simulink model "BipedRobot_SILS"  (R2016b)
settings: Solver=ode23tb  StartTime=0.0  StopTime=Tend  FixedStep=0.001  RelTol=1e-4  EnableMultiTasking=on
PreLoadFcn:
  | BipedRobot_param
  | load walk_forward
  | eta = 1;
  | N = 40;
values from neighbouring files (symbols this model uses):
  A = [1 0 0 0 0 0    [symbolic_sample.m]
  bn = 50    [BipedRobot_param.m]    (also in SimpleContact_param.m)
  bt = 50    [BipedRobot_param.m]    (also in SimpleContact_param.m)
  kn = 5000    [BipedRobot_param.m]    (also in SimpleContact_param.m)
  kt = 5000    [BipedRobot_param.m]    (also in SimpleContact_param.m)
  mu_d = 0.8    [BipedRobot_param.m]    (also in SimpleContact_param.m)
  mu_s = 2    [BipedRobot_param.m]    (also in SimpleContact_param.m)
  s = robot_para.s    [kinematics_calc.m]    (also in plot_graph.m; robot_parameter.m = 40; robot_view.m)
  Ts = walk_para.Ts    [Angular_Vel_Acc_calc_forward.m]    (also in main.m; reference_orbit.m; reference_orbit_acc.m; Vel_Acc_calc_forward.m)
  zvt = 1e-3    (= 0.001)    [BipedRobot_param.m]    (also in SimpleContact_param.m)
undefined symbols (not defined in the file or in its folder): arm, bridge, constant, deg, Inertia, KD, kg, KI, KP, m, Mass, powergui, pulses, rad, S, Torque
libraries: mblibv1 x90, powerlib x7, simulink x2, powerlib_extras x1
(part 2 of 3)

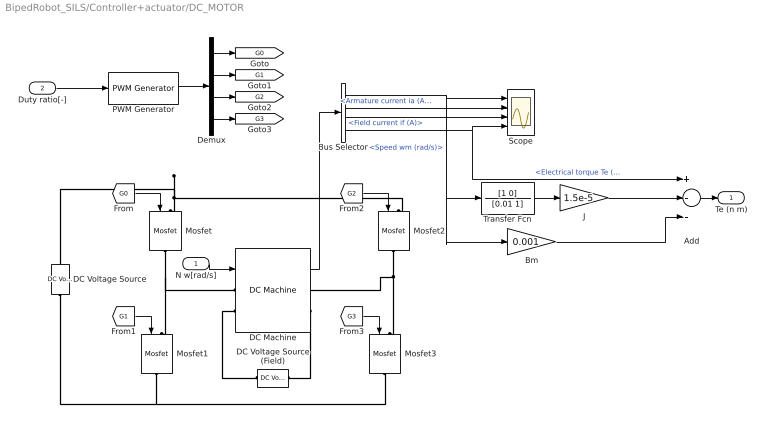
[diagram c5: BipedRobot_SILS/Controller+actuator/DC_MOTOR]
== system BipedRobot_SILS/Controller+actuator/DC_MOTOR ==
  N w[rad/s] : Inport
  Duty ratio[-] : Inport  Port=2
  Add : Sum  Inputs=+--
  Bm : Gain  Gain=0.001
  Bus Selector : BusSelector  OutputSignals=Speed wm (rad/s),Armature current ia (A),Field current if (A),Electrical torque Te (n m)
  DC Machine : powerlib/Machines/DC Machine  PresetModel=No  MechanicalLoad=Speed w  FieldType=Wound  ShowDetailedParameters=on  MeasurementBus=off  RLa="[ 10  4.4e-3]"  RLf="[ 24  0 ]"  Laf=0.05  MachineConstant=Torque constant (N.m/A)  Ke=1.8  Kt=1.8  J=1.5e-5  Bm=0.001  Tf=0  w0=0  Ifinit=1  TsPowergui=0  TsBlock=-1
  DC Voltage Source : powerlib/Electrical Sources/DC Voltage Source  Amplitude=24  Measurements=None
  DC Voltage Source (Field) : powerlib/Electrical Sources/DC Voltage Source  Amplitude=24  Measurements=None
  Demux : Demux
  J : Gain  Gain=1.5e-5
  Mosfet{,1..3} (4 alike) : powerlib/Power Electronics/Mosfet  Ron=0.3  Lon=0  Rd=0.01  Vfd=0  IC=0  Rs=5e9  Cs=inf  Measurements=off
  PWM Generator : powerlib_extras/Control  Blocks/PWM Generator  GeneratorMode="2-arm  bridge (4 pulses)"  Fc=1000  Internal=off  mIndex=0.4  Freq=60  Phase=0
  Scope : Scope  NumInputPorts=4
  Transfer Fcn : TransferFcn  Numerator=[1 0]  Denominator=[0.01 1]
  Te (n m) : Outport
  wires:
  Duty ratio[-]/1 -> PWM Generator/1
  PWM Generator/1 -> Demux/1
  [G2] -> Mosfet2/1
  [G1] -> Mosfet1/1
  [G0] -> Mosfet/1
  Demux/4 -> [G3]
  Demux/3 -> [G2]
  Demux/2 -> [G1]
  Demux/1 -> [G0]
  Bus Selector/1 -> Scope/1, Bm/1, Transfer Fcn/1  "<Speed wm (rad/s)>"
  Bus Selector/2 -> Scope/2  "<Armature current ia (A)>"
  [G3] -> Mosfet3/1
  N w[rad/s]/1 -> DC Machine/1
  DC Machine/1 -> Bus Selector/1
  Bus Selector/3 -> Scope/3  "<Field current if (A)>"
  Bus Selector/4 -> Scope/4, Add/1  "<Electrical torque Te (n m)>"
  Bm/1 -> Add/3
  Transfer Fcn/1 -> J/1
  Add/1 -> Te (n m)/1
  J/1 -> Add/2
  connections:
  Mosfet2/RConn1 -- Mosfet3/LConn1 -- DC Machine/RConn1
  Mosfet/RConn1 -- Mosfet1/LConn1 -- DC Machine/LConn1
  Mosfet/LConn1 -- Mosfet2/LConn1 -- DC Voltage Source/RConn1
  Mosfet1/RConn1 -- Mosfet3/RConn1 -- DC Voltage Source/LConn1
  DC Voltage Source (Field)/RConn1 -- DC Machine/LConn2
  DC Machine/RConn2 -- DC Voltage Source (Field)/LConn1

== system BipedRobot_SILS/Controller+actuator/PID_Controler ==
  In1 : Inport
  In2 : Inport  Port=2
  PIDコントローラ : Subsystem
  PIDコントローラ1 : Subsystem
  Scope : Scope
  Subtract : Sum  Inputs=+-
  正規化 : Subsystem
  角度-カウント値変換1 : Subsystem
  角度-カウント値変換2 : Subsystem
  Out1 : Outport
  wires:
  In1/1 -> 角度-カウント値変換1/1(theta[deg])
  PIDコントローラ/1(out) -> 正規化/1(In1), Subtract/1
  角度-カウント値変換2/1(count[-]) -> PIDコントローラ1/2(pos), PIDコントローラ/2(pos)
  角度-カウント値変換1/1(count[-]) -> PIDコントローラ1/1(ref), PIDコントローラ/1(ref)
  In2/1 -> 角度-カウント値変換2/1(theta[deg])
  PIDコントローラ1/1(out) -> Subtract/2
  Subtract/1 -> Scope/1
  正規化/1(Out1) -> Out1/1

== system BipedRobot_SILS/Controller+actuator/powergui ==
  note: Graphical user interface for the analysis of SimPowerSystems circuits. Place the Powergui block in the top-level of your model and double-click on it to open the GUI.
  EquivalentModel1 : Subsystem
  EquivalentModel2 : Subsystem
  Ground : Ground
  Terminator : Terminator
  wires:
  Ground/1 -> Terminator/1

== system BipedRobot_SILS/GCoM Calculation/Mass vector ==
  Constant : Constant  Value=Mass.RL0
  Constant1 : Constant  Value=Mass.RL1
  Constant10 : Constant  Value=Mass.LL4
  Constant11 : Constant  Value=Mass.LL5
  Constant12 : Constant  Value=Mass.WAIST
  Constant2 : Constant  Value=Mass.RL2
  Constant3 : Constant  Value=Mass.RL3
  Constant4 : Constant  Value=Mass.RL4
  Constant5 : Constant  Value=Mass.RL5
  Constant6 : Constant  Value=Mass.LL0
  Constant7 : Constant  Value=Mass.LL1
  Constant8 : Constant  Value=Mass.LL2
  Constant9 : Constant  Value=Mass.LL3
  Mux : Mux  Inputs=13
  Mvec : Outport
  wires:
  Constant7/1 -> Mux/8
  Constant6/1 -> Mux/7
  Constant5/1 -> Mux/6
  Constant4/1 -> Mux/5
  Constant3/1 -> Mux/4
  Constant2/1 -> Mux/3
  Constant1/1 -> Mux/2
  Constant/1 -> Mux/1
  Constant8/1 -> Mux/9
  Constant9/1 -> Mux/10
  Constant10/1 -> Mux/11
  Constant11/1 -> Mux/12
  Constant12/1 -> Mux/13
  Mux/1 -> Mvec/1

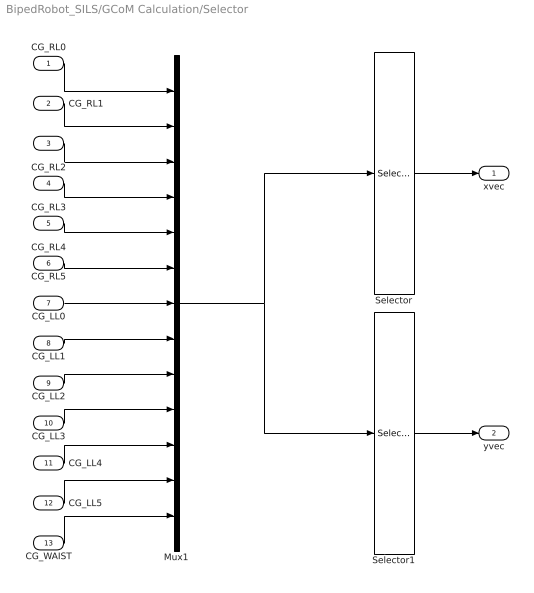
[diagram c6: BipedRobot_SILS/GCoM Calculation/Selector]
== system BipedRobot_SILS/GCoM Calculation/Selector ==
  CG_RL0 : Inport
  CG_RL1 : Inport  Port=2
  CG_RL2 : Inport  Port=3
  CG_RL3 : Inport  Port=4
  CG_RL4 : Inport  Port=5
  CG_RL5 : Inport  Port=6
  CG_LL0 : Inport  Port=7
  CG_LL1 : Inport  Port=8
  CG_LL2 : Inport  Port=9
  CG_LL3 : Inport  Port=10
  CG_LL4 : Inport  Port=11
  CG_LL5 : Inport  Port=12
  CG_WAIST : Inport  Port=13
  Mux1 : Mux  Inputs=13
  Selector : Selector  InputPortWidth=39  IndexOptions=Index vector (dialog)  Indices=1:3:39  OutputSizes=1
  Selector1 : Selector  InputPortWidth=39  IndexOptions=Index vector (dialog)  Indices=2:3:39  OutputSizes=1
  xvec : Outport
  yvec : Outport  Port=2
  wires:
  CG_RL0/1 -> Mux1/1
  CG_RL1/1 -> Mux1/2
  CG_RL2/1 -> Mux1/3
  CG_RL3/1 -> Mux1/4
  CG_RL4/1 -> Mux1/5
  CG_RL5/1 -> Mux1/6
  CG_LL0/1 -> Mux1/7
  CG_LL1/1 -> Mux1/8
  CG_LL2/1 -> Mux1/9
  CG_LL3/1 -> Mux1/10
  CG_LL4/1 -> Mux1/11
  CG_LL5/1 -> Mux1/12
  CG_WAIST/1 -> Mux1/13
  Mux1/1 -> Selector/1, Selector1/1
  Selector/1 -> xvec/1
  Selector1/1 -> yvec/1

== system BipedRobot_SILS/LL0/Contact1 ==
  Body Actuator : mblibv1/Sensors &  Actuators/Body Actuator  UpdateFromCAD=off  PhysicalDomain=Mechanical  PortType=blob  ActuationStyle=Force  AngleUnits=deg  ArcVelocityUnits=deg/s  ArcAccelerationUnits=deg/s^2  CoordPositionUnits=m  VelocityUnits=m/s  AccelerationUnits=m/s^2  ForceUnits=N  TorqueUnits=N-m  ActiveIO=on  Width=3  DialogClass=MechanicalActuatorBlock  ReferenceFrame=Absolute (World)  Angle=off  CoordPosition=on  Force=on  Torque=off
  Body Sensor : mblibv1/Sensors &  Actuators/Body Sensor  UpdateFromCAD=off  PhysicalDomain=Mechanical  PortType=blob  Muxed=off  Pose=off  Angle=on  AngleUnits=deg  ArcVelocity=off  ArcVelocityUnits=deg/s  ArcAcceleration=off  ArcAccelerationUnits=deg/s^2  CoordPosition=on  CoordPositionUnits=m  Velocity=on  VelocityUnits=m/s  Acceleration=off  AccelerationUnits=m/s^2  Quaternion=on  QuaternionDT=off  QuaternionDDT=off  QuaternionUnits=off  OutputVector=[ 3 3 ]  ActiveIO=on  Width=6  DialogClass=MechanicalSensorBlock  ReferenceFrame=Absolute (World)
  Contact Force : Subsystem
  Mechanical Branching Bar : mblibv1/Utilities/Mechanical Branching Bar  LConnTagsString=_newl0  RConnTagsString=SA0|SA1  UpdateFromCAD=off  DialogClass=MechanicalBranchingBarBlock  NumSAPorts=2
  CS : PMIOPort  Port=1  Side=Right
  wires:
  Body Sensor/1 -> [posL_FrontRight], Contact Force/1(pos)
  Body Sensor/2 -> Contact Force/2(vel)
  Contact Force/1(force) -> Body Actuator/1
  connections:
  Mechanical Branching Bar/RConn1 -- Body Sensor/LConn1
  Mechanical Branching Bar/RConn2 -- Body Actuator/RConn1
  CS/RConn1 -- Mechanical Branching Bar/LConn1

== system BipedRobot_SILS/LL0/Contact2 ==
  Body Actuator : mblibv1/Sensors &  Actuators/Body Actuator  UpdateFromCAD=off  PhysicalDomain=Mechanical  PortType=blob  ActuationStyle=Force  AngleUnits=deg  ArcVelocityUnits=deg/s  ArcAccelerationUnits=deg/s^2  CoordPositionUnits=m  VelocityUnits=m/s  AccelerationUnits=m/s^2  ForceUnits=N  TorqueUnits=N-m  ActiveIO=on  Width=3  DialogClass=MechanicalActuatorBlock  ReferenceFrame=Absolute (World)  Angle=off  CoordPosition=on  Force=on  Torque=off
  Body Sensor : mblibv1/Sensors &  Actuators/Body Sensor  UpdateFromCAD=off  PhysicalDomain=Mechanical  PortType=blob  Muxed=off  Pose=off  Angle=on  AngleUnits=deg  ArcVelocity=off  ArcVelocityUnits=deg/s  ArcAcceleration=off  ArcAccelerationUnits=deg/s^2  CoordPosition=on  CoordPositionUnits=m  Velocity=on  VelocityUnits=m/s  Acceleration=off  AccelerationUnits=m/s^2  Quaternion=on  QuaternionDT=off  QuaternionDDT=off  QuaternionUnits=off  OutputVector=[ 3 3 ]  ActiveIO=on  Width=6  DialogClass=MechanicalSensorBlock  ReferenceFrame=Absolute (World)
  Contact Force : Subsystem
  Mechanical Branching Bar : mblibv1/Utilities/Mechanical Branching Bar  LConnTagsString=_newl0  RConnTagsString=SA0|SA1  UpdateFromCAD=off  DialogClass=MechanicalBranchingBarBlock  NumSAPorts=2
  CS : PMIOPort  Port=1  Side=Right
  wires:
  Contact Force/1(force) -> Body Actuator/1
  Body Sensor/2 -> Contact Force/2(vel)
  Body Sensor/1 -> [posL_RearRight], Contact Force/1(pos)
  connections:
  CS/RConn1 -- Mechanical Branching Bar/LConn1
  Mechanical Branching Bar/RConn2 -- Body Actuator/RConn1
  Mechanical Branching Bar/RConn1 -- Body Sensor/LConn1

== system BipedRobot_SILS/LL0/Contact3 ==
  Body Actuator : mblibv1/Sensors &  Actuators/Body Actuator  UpdateFromCAD=off  PhysicalDomain=Mechanical  PortType=blob  ActuationStyle=Force  AngleUnits=deg  ArcVelocityUnits=deg/s  ArcAccelerationUnits=deg/s^2  CoordPositionUnits=m  VelocityUnits=m/s  AccelerationUnits=m/s^2  ForceUnits=N  TorqueUnits=N-m  ActiveIO=on  Width=3  DialogClass=MechanicalActuatorBlock  ReferenceFrame=Absolute (World)  Angle=off  CoordPosition=on  Force=on  Torque=off
  Body Sensor : mblibv1/Sensors &  Actuators/Body Sensor  UpdateFromCAD=off  PhysicalDomain=Mechanical  PortType=blob  Muxed=off  Pose=off  Angle=on  AngleUnits=deg  ArcVelocity=off  ArcVelocityUnits=deg/s  ArcAcceleration=off  ArcAccelerationUnits=deg/s^2  CoordPosition=on  CoordPositionUnits=m  Velocity=on  VelocityUnits=m/s  Acceleration=off  AccelerationUnits=m/s^2  Quaternion=on  QuaternionDT=off  QuaternionDDT=off  QuaternionUnits=off  OutputVector=[ 3 3 ]  ActiveIO=on  Width=6  DialogClass=MechanicalSensorBlock  ReferenceFrame=Absolute (World)
  Contact Force : Subsystem
  Mechanical Branching Bar : mblibv1/Utilities/Mechanical Branching Bar  LConnTagsString=_newl0  RConnTagsString=SA0|SA1  UpdateFromCAD=off  DialogClass=MechanicalBranchingBarBlock  NumSAPorts=2
  CS : PMIOPort  Port=1  Side=Right
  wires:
  Contact Force/1(force) -> Body Actuator/1
  Body Sensor/2 -> Contact Force/2(vel)
  Body Sensor/1 -> [posL_FrontLeft], Contact Force/1(pos)
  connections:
  CS/RConn1 -- Mechanical Branching Bar/LConn1
  Mechanical Branching Bar/RConn2 -- Body Actuator/RConn1
  Mechanical Branching Bar/RConn1 -- Body Sensor/LConn1

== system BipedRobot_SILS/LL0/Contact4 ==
  Body Actuator : mblibv1/Sensors &  Actuators/Body Actuator  UpdateFromCAD=off  PhysicalDomain=Mechanical  PortType=blob  ActuationStyle=Force  AngleUnits=deg  ArcVelocityUnits=deg/s  ArcAccelerationUnits=deg/s^2  CoordPositionUnits=m  VelocityUnits=m/s  AccelerationUnits=m/s^2  ForceUnits=N  TorqueUnits=N-m  ActiveIO=on  Width=3  DialogClass=MechanicalActuatorBlock  ReferenceFrame=Absolute (World)  Angle=off  CoordPosition=on  Force=on  Torque=off
  Body Sensor : mblibv1/Sensors &  Actuators/Body Sensor  UpdateFromCAD=off  PhysicalDomain=Mechanical  PortType=blob  Muxed=off  Pose=off  Angle=on  AngleUnits=deg  ArcVelocity=off  ArcVelocityUnits=deg/s  ArcAcceleration=off  ArcAccelerationUnits=deg/s^2  CoordPosition=on  CoordPositionUnits=m  Velocity=on  VelocityUnits=m/s  Acceleration=off  AccelerationUnits=m/s^2  Quaternion=on  QuaternionDT=off  QuaternionDDT=off  QuaternionUnits=off  OutputVector=[ 3 3 ]  ActiveIO=on  Width=6  DialogClass=MechanicalSensorBlock  ReferenceFrame=Absolute (World)
  Contact Force : Subsystem
  Mechanical Branching Bar : mblibv1/Utilities/Mechanical Branching Bar  LConnTagsString=_newl0  RConnTagsString=SA0|SA1  UpdateFromCAD=off  DialogClass=MechanicalBranchingBarBlock  NumSAPorts=2
  CS : PMIOPort  Port=1  Side=Right
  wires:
  Body Sensor/1 -> [posL_RearLeft], Contact Force/1(pos)
  Body Sensor/2 -> Contact Force/2(vel)
  Contact Force/1(force) -> Body Actuator/1
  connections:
  Mechanical Branching Bar/RConn1 -- Body Sensor/LConn1
  Mechanical Branching Bar/RConn2 -- Body Actuator/RConn1
  CS/RConn1 -- Mechanical Branching Bar/LConn1

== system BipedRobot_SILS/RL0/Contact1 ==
  Body Actuator : mblibv1/Sensors &  Actuators/Body Actuator  UpdateFromCAD=off  PhysicalDomain=Mechanical  PortType=blob  ActuationStyle=Force  AngleUnits=deg  ArcVelocityUnits=deg/s  ArcAccelerationUnits=deg/s^2  CoordPositionUnits=m  VelocityUnits=m/s  AccelerationUnits=m/s^2  ForceUnits=N  TorqueUnits=N-m  ActiveIO=on  Width=3  DialogClass=MechanicalActuatorBlock  ReferenceFrame=Absolute (World)  Angle=off  CoordPosition=on  Force=on  Torque=off
  Body Sensor : mblibv1/Sensors &  Actuators/Body Sensor  UpdateFromCAD=off  PhysicalDomain=Mechanical  PortType=blob  Muxed=off  Pose=off  Angle=on  AngleUnits=deg  ArcVelocity=off  ArcVelocityUnits=deg/s  ArcAcceleration=off  ArcAccelerationUnits=deg/s^2  CoordPosition=on  CoordPositionUnits=m  Velocity=on  VelocityUnits=m/s  Acceleration=off  AccelerationUnits=m/s^2  Quaternion=on  QuaternionDT=off  QuaternionDDT=off  QuaternionUnits=off  OutputVector=[ 3 3 ]  ActiveIO=on  Width=6  DialogClass=MechanicalSensorBlock  ReferenceFrame=Absolute (World)
  Contact Force : Subsystem
  Mechanical Branching Bar : mblibv1/Utilities/Mechanical Branching Bar  LConnTagsString=_newl0  RConnTagsString=SA0|SA1  UpdateFromCAD=off  DialogClass=MechanicalBranchingBarBlock  NumSAPorts=2
  CS : PMIOPort  Port=1  Side=Right
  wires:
  Contact Force/1(force) -> Body Actuator/1
  Body Sensor/2 -> Contact Force/2(vel)
  Body Sensor/1 -> [posR_FrontLeft], Contact Force/1(pos)
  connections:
  CS/RConn1 -- Mechanical Branching Bar/LConn1
  Mechanical Branching Bar/RConn2 -- Body Actuator/RConn1
  Mechanical Branching Bar/RConn1 -- Body Sensor/LConn1

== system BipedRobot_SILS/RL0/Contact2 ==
  Body Actuator : mblibv1/Sensors &  Actuators/Body Actuator  UpdateFromCAD=off  PhysicalDomain=Mechanical  PortType=blob  ActuationStyle=Force  AngleUnits=deg  ArcVelocityUnits=deg/s  ArcAccelerationUnits=deg/s^2  CoordPositionUnits=m  VelocityUnits=m/s  AccelerationUnits=m/s^2  ForceUnits=N  TorqueUnits=N-m  ActiveIO=on  Width=3  DialogClass=MechanicalActuatorBlock  ReferenceFrame=Absolute (World)  Angle=off  CoordPosition=on  Force=on  Torque=off
  Body Sensor : mblibv1/Sensors &  Actuators/Body Sensor  UpdateFromCAD=off  PhysicalDomain=Mechanical  PortType=blob  Muxed=off  Pose=off  Angle=on  AngleUnits=deg  ArcVelocity=off  ArcVelocityUnits=deg/s  ArcAcceleration=off  ArcAccelerationUnits=deg/s^2  CoordPosition=on  CoordPositionUnits=m  Velocity=on  VelocityUnits=m/s  Acceleration=off  AccelerationUnits=m/s^2  Quaternion=on  QuaternionDT=off  QuaternionDDT=off  QuaternionUnits=off  OutputVector=[ 3 3 ]  ActiveIO=on  Width=6  DialogClass=MechanicalSensorBlock  ReferenceFrame=Absolute (World)
  Contact Force : Subsystem
  Mechanical Branching Bar : mblibv1/Utilities/Mechanical Branching Bar  LConnTagsString=_newl0  RConnTagsString=SA0|SA1  UpdateFromCAD=off  DialogClass=MechanicalBranchingBarBlock  NumSAPorts=2
  CS : PMIOPort  Port=1  Side=Right
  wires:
  Body Sensor/1 -> [posR_RearLeft], Contact Force/1(pos)
  Body Sensor/2 -> Contact Force/2(vel)
  Contact Force/1(force) -> Body Actuator/1
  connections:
  Mechanical Branching Bar/RConn1 -- Body Sensor/LConn1
  Mechanical Branching Bar/RConn2 -- Body Actuator/RConn1
  CS/RConn1 -- Mechanical Branching Bar/LConn1

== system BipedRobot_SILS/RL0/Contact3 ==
  Body Actuator : mblibv1/Sensors &  Actuators/Body Actuator  UpdateFromCAD=off  PhysicalDomain=Mechanical  PortType=blob  ActuationStyle=Force  AngleUnits=deg  ArcVelocityUnits=deg/s  ArcAccelerationUnits=deg/s^2  CoordPositionUnits=m  VelocityUnits=m/s  AccelerationUnits=m/s^2  ForceUnits=N  TorqueUnits=N-m  ActiveIO=on  Width=3  DialogClass=MechanicalActuatorBlock  ReferenceFrame=Absolute (World)  Angle=off  CoordPosition=on  Force=on  Torque=off
  Body Sensor : mblibv1/Sensors &  Actuators/Body Sensor  UpdateFromCAD=off  PhysicalDomain=Mechanical  PortType=blob  Muxed=off  Pose=off  Angle=on  AngleUnits=deg  ArcVelocity=off  ArcVelocityUnits=deg/s  ArcAcceleration=off  ArcAccelerationUnits=deg/s^2  CoordPosition=on  CoordPositionUnits=m  Velocity=on  VelocityUnits=m/s  Acceleration=off  AccelerationUnits=m/s^2  Quaternion=on  QuaternionDT=off  QuaternionDDT=off  QuaternionUnits=off  OutputVector=[ 3 3 ]  ActiveIO=on  Width=6  DialogClass=MechanicalSensorBlock  ReferenceFrame=Absolute (World)
  Contact Force : Subsystem
  Mechanical Branching Bar : mblibv1/Utilities/Mechanical Branching Bar  LConnTagsString=_newl0  RConnTagsString=SA0|SA1  UpdateFromCAD=off  DialogClass=MechanicalBranchingBarBlock  NumSAPorts=2
  CS : PMIOPort  Port=1  Side=Right
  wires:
  Body Sensor/1 -> [posR_FrontRight], Contact Force/1(pos)
  Body Sensor/2 -> Contact Force/2(vel)
  Contact Force/1(force) -> Body Actuator/1
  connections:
  Mechanical Branching Bar/RConn1 -- Body Sensor/LConn1
  Mechanical Branching Bar/RConn2 -- Body Actuator/RConn1
  CS/RConn1 -- Mechanical Branching Bar/LConn1

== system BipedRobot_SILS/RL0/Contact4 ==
  Body Actuator : mblibv1/Sensors &  Actuators/Body Actuator  UpdateFromCAD=off  PhysicalDomain=Mechanical  PortType=blob  ActuationStyle=Force  AngleUnits=deg  ArcVelocityUnits=deg/s  ArcAccelerationUnits=deg/s^2  CoordPositionUnits=m  VelocityUnits=m/s  AccelerationUnits=m/s^2  ForceUnits=N  TorqueUnits=N-m  ActiveIO=on  Width=3  DialogClass=MechanicalActuatorBlock  ReferenceFrame=Absolute (World)  Angle=off  CoordPosition=on  Force=on  Torque=off
  Body Sensor : mblibv1/Sensors &  Actuators/Body Sensor  UpdateFromCAD=off  PhysicalDomain=Mechanical  PortType=blob  Muxed=off  Pose=off  Angle=on  AngleUnits=deg  ArcVelocity=off  ArcVelocityUnits=deg/s  ArcAcceleration=off  ArcAccelerationUnits=deg/s^2  CoordPosition=on  CoordPositionUnits=m  Velocity=on  VelocityUnits=m/s  Acceleration=off  AccelerationUnits=m/s^2  Quaternion=on  QuaternionDT=off  QuaternionDDT=off  QuaternionUnits=off  OutputVector=[ 3 3 ]  ActiveIO=on  Width=6  DialogClass=MechanicalSensorBlock  ReferenceFrame=Absolute (World)
  Contact Force : Subsystem
  Mechanical Branching Bar : mblibv1/Utilities/Mechanical Branching Bar  LConnTagsString=_newl0  RConnTagsString=SA0|SA1  UpdateFromCAD=off  DialogClass=MechanicalBranchingBarBlock  NumSAPorts=2
  CS : PMIOPort  Port=1  Side=Right
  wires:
  Contact Force/1(force) -> Body Actuator/1
  Body Sensor/2 -> Contact Force/2(vel)
  Body Sensor/1 -> [posR_RearRight], Contact Force/1(pos)
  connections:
  CS/RConn1 -- Mechanical Branching Bar/LConn1
  Mechanical Branching Bar/RConn2 -- Body Actuator/RConn1
  Mechanical Branching Bar/RConn1 -- Body Sensor/LConn1

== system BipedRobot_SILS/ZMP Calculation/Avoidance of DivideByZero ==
  u : Inport
  Compare To Zero : simulink/Logic and Bit Operations/Compare To Zero  relop===  OutDataTypeStr=boolean  ZeroCross=off
  Constant : Constant
  Switch : Switch  Criteria=u2 > Threshold  Threshold=0.5
  y : Outport
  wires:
  Compare To Zero/1 -> Switch/2
  u/1 -> Compare To Zero/1, Switch/3
  Constant/1 -> Switch/1
  Switch/1 -> y/1

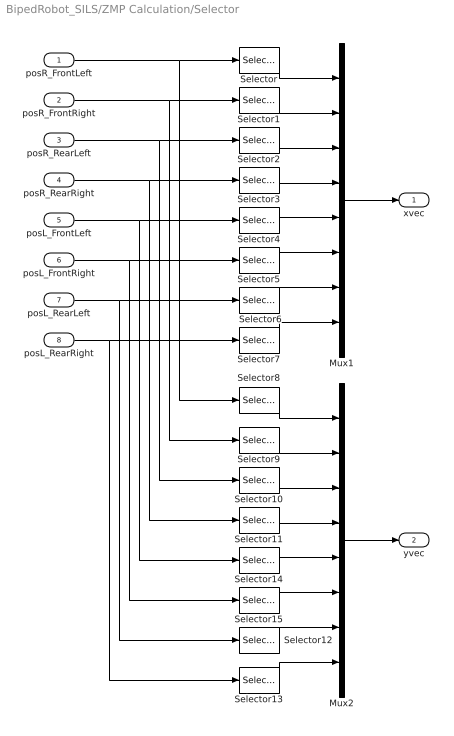
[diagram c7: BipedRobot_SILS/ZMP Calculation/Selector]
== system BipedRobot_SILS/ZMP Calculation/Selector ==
  posR_FrontLeft : Inport
  posR_FrontRight : Inport  Port=2
  posR_RearLeft : Inport  Port=3
  posR_RearRight : Inport  Port=4
  posL_FrontLeft : Inport  Port=5
  posL_FrontRight : Inport  Port=6
  posL_RearLeft : Inport  Port=7
  posL_RearRight : Inport  Port=8
  Mux1 : Mux  Inputs=8
  Mux2 : Mux  Inputs=8
  Selector{,1..7} (8 alike) : Selector  InputPortWidth=3  IndexOptions=Index vector (dialog)  Indices=1  OutputSizes=1
  Selector{8..15} (8 alike) : Selector  InputPortWidth=3  IndexOptions=Index vector (dialog)  Indices=2  OutputSizes=1
  xvec : Outport
  yvec : Outport  Port=2
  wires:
  posR_FrontLeft/1 -> Selector8/1, Selector/1
  posR_FrontRight/1 -> Selector9/1, Selector1/1
  posR_RearLeft/1 -> Selector10/1, Selector2/1
  posR_RearRight/1 -> Selector11/1, Selector3/1
  posL_FrontLeft/1 -> Selector14/1, Selector4/1
  posL_FrontRight/1 -> Selector15/1, Selector5/1
  posL_RearLeft/1 -> Selector12/1, Selector6/1
  posL_RearRight/1 -> Selector13/1, Selector7/1
  Selector/1 -> Mux1/1
  Selector1/1 -> Mux1/2
  Selector2/1 -> Mux1/3
  Selector3/1 -> Mux1/4
  Selector4/1 -> Mux1/5
  Selector5/1 -> Mux1/6
  Selector6/1 -> Mux1/7
  Selector7/1 -> Mux1/8
  Selector8/1 -> Mux2/1
  Selector9/1 -> Mux2/2
  Selector10/1 -> Mux2/3
  Selector11/1 -> Mux2/4
  Selector14/1 -> Mux2/5
  Selector15/1 -> Mux2/6
  Selector12/1 -> Mux2/7
  Selector13/1 -> Mux2/8
  Mux1/1 -> xvec/1
  Mux2/1 -> yvec/1

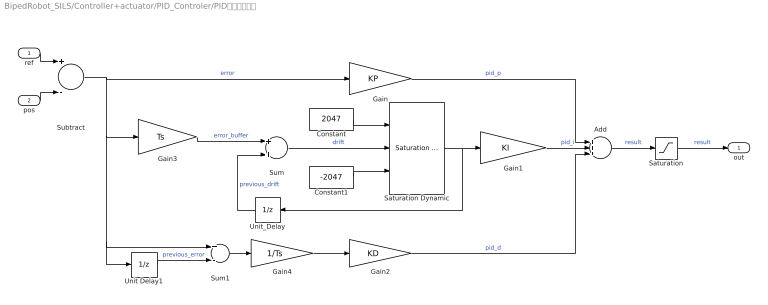
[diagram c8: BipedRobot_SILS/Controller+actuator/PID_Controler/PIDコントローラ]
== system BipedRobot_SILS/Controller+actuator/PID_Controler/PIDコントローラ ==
  ref : Inport
  pos : Inport  Port=2
  Add : Sum  Inputs=+++  OutDataTypeStr=double
  Constant : Constant  Value=2047  SampleTime=Ts
  Constant1 : Constant  Value=-2047  SampleTime=Ts
  Gain : Gain  Gain=KP  RndMeth=Zero
  Gain1 : Gain  Gain=KI  RndMeth=Zero
  Gain2 : Gain  Gain=KD  RndMeth=Zero
  Gain3 : Gain  Gain=Ts
  Gain4 : Gain  Gain=1/Ts  RndMeth=Zero
  Saturation : Saturate  UpperLimit=2047  LowerLimit=-2047
  Saturation Dynamic : simulink/Discontinuities/Saturation Dynamic  OutMin=[]  OutMax=[]  OutDataTypeStr=Inherit: Same as second input  OutDataType=fixdt(1, 16)  OutScaling=2^-10  DoSatur=off
  Subtract : Sum  Inputs=+-  OutDataTypeStr=double
  Sum : Sum  OutDataTypeStr=double
  Sum1 : Sum  Inputs=+-  OutDataTypeStr=double
  Unit Delay1 : UnitDelay  SampleTime=Ts
  Unit_Delay : UnitDelay  SampleTime=Ts
  out : Outport
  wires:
  pos/1 -> Subtract/2
  Saturation/1 -> out/1  "result"
  Gain3/1 -> Sum/1  "error_buffer"
  ref/1 -> Subtract/1
  Subtract/1 -> Gain/1, Unit Delay1/1, Sum1/1, Gain3/1  "error"
  Sum/1 -> Saturation Dynamic/2  "drift"
  Unit_Delay/1 -> Sum/2  "previous_drift"
  Unit Delay1/1 -> Sum1/2  "previous_error"
  Sum1/1 -> Gain4/1
  Add/1 -> Saturation/1  "result"
  Constant1/1 -> Saturation Dynamic/3
  Constant/1 -> Saturation Dynamic/1
  Gain/1 -> Add/1  "pid_p"
  Gain2/1 -> Add/3  "pid_d"
  Saturation Dynamic/1 -> Unit_Delay/1, Gain1/1
  Gain4/1 -> Gain2/1
  Gain1/1 -> Add/2  "pid_i"

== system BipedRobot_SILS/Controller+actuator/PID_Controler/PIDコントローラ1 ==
  ref : Inport
  pos : Inport  Port=2
  PIDコントローラ_sfcn : S-Function  FunctionName=PID0_sf  SFunctionModules=""  SFunctionDeploymentMode=off  EnableBusSupport=off  SFcnStateName=DWORK0
  __InputSSForSFun__ : Subsystem
  __OutputSSForSFun__ : Subsystem
  out : Outport
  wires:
  ref/1 -> __InputSSForSFun__/1(ref)
  pos/1 -> __InputSSForSFun__/2(pos)
  __InputSSForSFun__/1(__UniqueOutportName__1__) -> PIDコントローラ_sfcn/1
  __InputSSForSFun__/2(__UniqueOutportName__2__) -> PIDコントローラ_sfcn/2
  PIDコントローラ_sfcn/1 -> __OutputSSForSFun__/1(__UniqueInportName__1__)
  __OutputSSForSFun__/1(out) -> out/1

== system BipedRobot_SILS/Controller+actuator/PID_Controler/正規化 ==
  note: PID制御器の出力を補正して最大1最小-1（double）とする。
  note: PID制御器の出力 最大2047最小-2047
  note: 符号ビット1+11ビットで 表現できる最大数
  In1 : Inport
  Gain1 : Gain  Gain=1/2047
  Out1 : Outport
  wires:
  Gain1/1 -> Out1/1
  In1/1 -> Gain1/1

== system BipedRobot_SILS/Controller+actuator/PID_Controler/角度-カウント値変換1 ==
  note: カウント値[-]= (50+50/180*角度[deg])*1023/100
  theta[deg] : Inport
  Add : Sum
  Constant : Constant  Value=50
  Constant1 : Constant  Value=180
  Constant2 : Constant  Value=50
  Constant3 : Constant  Value=1023
  Constant4 : Constant  Value=100
  Divide : Product  Inputs=**/
  Divide1 : Product  Inputs=**/
  count[-] : Outport
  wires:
  Divide1/1 -> count[-]/1
  theta[deg]/1 -> Divide/1
  Constant4/1 -> Divide1/3
  Constant3/1 -> Divide1/2
  Add/1 -> Divide1/1
  Constant2/1 -> Add/2
  Divide/1 -> Add/1
  Constant1/1 -> Divide/3
  Constant/1 -> Divide/2

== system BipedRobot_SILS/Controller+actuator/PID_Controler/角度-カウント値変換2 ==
  note: カウント値[-]= (50+50/180*角度[deg])*1023/100
  theta[deg] : Inport
  Add : Sum
  Constant : Constant  Value=50
  Constant1 : Constant  Value=180
  Constant2 : Constant  Value=50
  Constant3 : Constant  Value=1023
  Constant4 : Constant  Value=100
  Divide : Product  Inputs=**/
  Divide1 : Product  Inputs=**/
  count[-] : Outport
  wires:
  Constant/1 -> Divide/2
  Constant1/1 -> Divide/3
  Divide/1 -> Add/1
  Constant2/1 -> Add/2
  Add/1 -> Divide1/1
  Constant3/1 -> Divide1/2
  Constant4/1 -> Divide1/3
  theta[deg]/1 -> Divide/1
  Divide1/1 -> count[-]/1

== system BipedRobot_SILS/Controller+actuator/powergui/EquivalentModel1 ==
  Sources : Subsystem
  State-Space : StateSpace  A=S.A  B=S.B  C=S.C  D=S.D  X0=S.x0
  Yout : Subsystem
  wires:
  Sources/1(u) -> State-Space/1
  State-Space/1 -> Yout/1(v,i)

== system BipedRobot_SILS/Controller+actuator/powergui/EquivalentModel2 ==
  Gates : Subsystem
  Sources : Subsystem
  State-Space : S-Function  FunctionName=sfun_spssw_contc  Parameters=S.A, S.B, S.C, S.D, S.x0, S.EnableUseOfTLC,S.SwitchResistance ,S.SwitchType, S.SwitchGateInitialValue, S.OutputsToResetToZero,S.SaveMatrices,S.BufferSize  SFunctionDeploymentMode=off  EnableBusSupport=off
  Status : Subsystem
  Yout : Subsystem
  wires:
  Gates/1(gates) -> State-Space/2
  Sources/1(u) -> State-Space/1
  State-Space/2 -> Status/1(status)
  State-Space/1 -> Yout/1(v,i)

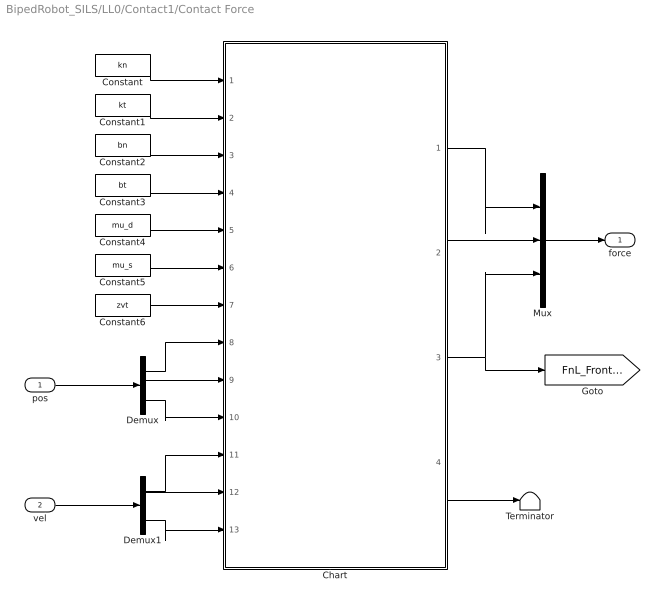
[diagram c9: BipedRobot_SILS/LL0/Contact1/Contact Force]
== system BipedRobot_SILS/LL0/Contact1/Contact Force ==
  pos : Inport
  vel : Inport  Port=2
  Chart : Stateflow chart  TreatAsAtomicUnit=on
  Constant : Constant  Value=kn
  Constant1 : Constant  Value=kt
  Constant2 : Constant  Value=bn
  Constant3 : Constant  Value=bt
  Constant4 : Constant  Value=mu_d
  Constant5 : Constant  Value=mu_s
  Constant6 : Constant  Value=zvt
  Demux : Demux  Outputs=3
  Demux1 : Demux  Outputs=3
  Mux : Mux  Inputs=3
  Terminator : Terminator
  force : Outport  InitialOutput=0
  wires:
  Chart/3(Fn) -> Mux/3, [FnL_FrontRight]
  Chart/2(Fy) -> Mux/2
  Chart/1(Fx) -> Mux/1
  vel/1 -> Demux1/1
  pos/1 -> Demux/1
  Demux1/3 -> Chart/13(dpn)
  Demux1/2 -> Chart/12(dpy)
  Demux1/1 -> Chart/11(dpx)
  Demux/3 -> Chart/10(pn)
  Demux/2 -> Chart/9(py)
  Demux/1 -> Chart/8(px)
  Chart/4(mode) -> Terminator/1
  Mux/1 -> force/1
  Constant/1 -> Chart/1(kn)
  Constant1/1 -> Chart/2(kt)
  Constant2/1 -> Chart/3(bn)
  Constant3/1 -> Chart/4(bt)
  Constant4/1 -> Chart/5(mu_d)
  Constant5/1 -> Chart/6(mu_s)
  Constant6/1 -> Chart/7(zvt)

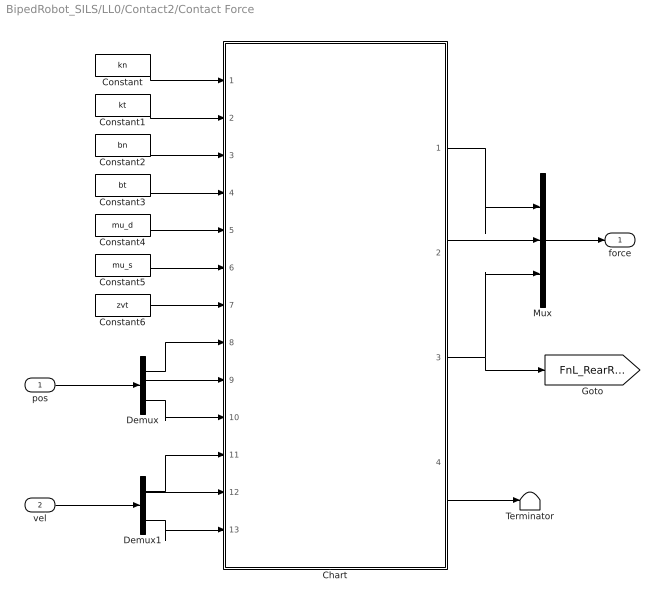
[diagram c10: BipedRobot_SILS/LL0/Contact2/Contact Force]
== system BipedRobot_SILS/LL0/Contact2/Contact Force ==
  pos : Inport
  vel : Inport  Port=2
  Chart : Stateflow chart  TreatAsAtomicUnit=on
  Constant : Constant  Value=kn
  Constant1 : Constant  Value=kt
  Constant2 : Constant  Value=bn
  Constant3 : Constant  Value=bt
  Constant4 : Constant  Value=mu_d
  Constant5 : Constant  Value=mu_s
  Constant6 : Constant  Value=zvt
  Demux : Demux  Outputs=3
  Demux1 : Demux  Outputs=3
  Mux : Mux  Inputs=3
  Terminator : Terminator
  force : Outport  InitialOutput=0
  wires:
  Chart/3(Fn) -> Mux/3, [FnL_RearRight]
  Chart/2(Fy) -> Mux/2
  Chart/1(Fx) -> Mux/1
  vel/1 -> Demux1/1
  pos/1 -> Demux/1
  Demux1/3 -> Chart/13(dpn)
  Demux1/2 -> Chart/12(dpy)
  Demux1/1 -> Chart/11(dpx)
  Demux/3 -> Chart/10(pn)
  Demux/2 -> Chart/9(py)
  Demux/1 -> Chart/8(px)
  Chart/4(mode) -> Terminator/1
  Mux/1 -> force/1
  Constant/1 -> Chart/1(kn)
  Constant1/1 -> Chart/2(kt)
  Constant2/1 -> Chart/3(bn)
  Constant3/1 -> Chart/4(bt)
  Constant4/1 -> Chart/5(mu_d)
  Constant5/1 -> Chart/6(mu_s)
  Constant6/1 -> Chart/7(zvt)

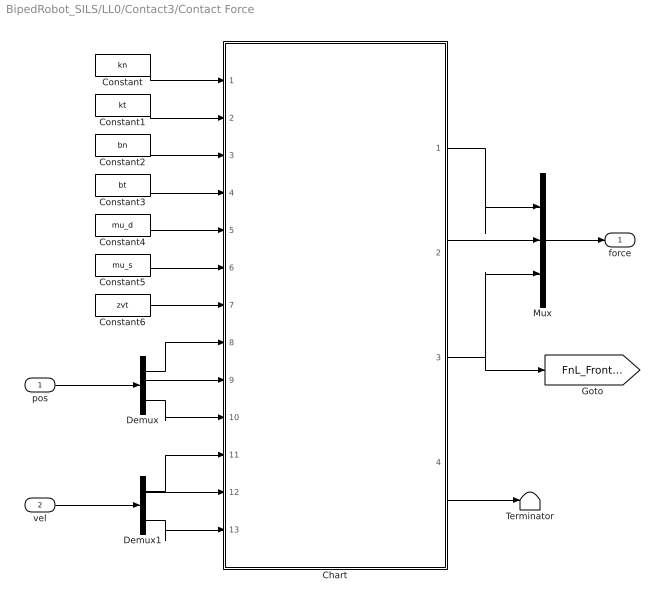
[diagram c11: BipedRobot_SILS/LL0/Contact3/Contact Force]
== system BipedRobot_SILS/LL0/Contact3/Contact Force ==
  pos : Inport
  vel : Inport  Port=2
  Chart : Stateflow chart  TreatAsAtomicUnit=on
  Constant : Constant  Value=kn
  Constant1 : Constant  Value=kt
  Constant2 : Constant  Value=bn
  Constant3 : Constant  Value=bt
  Constant4 : Constant  Value=mu_d
  Constant5 : Constant  Value=mu_s
  Constant6 : Constant  Value=zvt
  Demux : Demux  Outputs=3
  Demux1 : Demux  Outputs=3
  Mux : Mux  Inputs=3
  Terminator : Terminator
  force : Outport  InitialOutput=0
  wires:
  Chart/3(Fn) -> Mux/3, [FnL_FrontLeft]
  Chart/2(Fy) -> Mux/2
  Chart/1(Fx) -> Mux/1
  vel/1 -> Demux1/1
  pos/1 -> Demux/1
  Demux1/3 -> Chart/13(dpn)
  Demux1/2 -> Chart/12(dpy)
  Demux1/1 -> Chart/11(dpx)
  Demux/3 -> Chart/10(pn)
  Demux/2 -> Chart/9(py)
  Demux/1 -> Chart/8(px)
  Chart/4(mode) -> Terminator/1
  Mux/1 -> force/1
  Constant/1 -> Chart/1(kn)
  Constant1/1 -> Chart/2(kt)
  Constant2/1 -> Chart/3(bn)
  Constant3/1 -> Chart/4(bt)
  Constant4/1 -> Chart/5(mu_d)
  Constant5/1 -> Chart/6(mu_s)
  Constant6/1 -> Chart/7(zvt)

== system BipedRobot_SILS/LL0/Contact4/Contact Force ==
  pos : Inport
  vel : Inport  Port=2
  Chart : Stateflow chart  TreatAsAtomicUnit=on
  Constant : Constant  Value=kn
  Constant1 : Constant  Value=kt
  Constant2 : Constant  Value=bn
  Constant3 : Constant  Value=bt
  Constant4 : Constant  Value=mu_d
  Constant5 : Constant  Value=mu_s
  Constant6 : Constant  Value=zvt
  Demux : Demux  Outputs=3
  Demux1 : Demux  Outputs=3
  Mux : Mux  Inputs=3
  Terminator : Terminator
  force : Outport  InitialOutput=0
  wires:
  Chart/3(Fn) -> Mux/3, [FnL_RearLeft]
  Chart/2(Fy) -> Mux/2
  Chart/1(Fx) -> Mux/1
  vel/1 -> Demux1/1
  pos/1 -> Demux/1
  Demux1/3 -> Chart/13(dpn)
  Demux1/2 -> Chart/12(dpy)
  Demux1/1 -> Chart/11(dpx)
  Demux/3 -> Chart/10(pn)
  Demux/2 -> Chart/9(py)
  Demux/1 -> Chart/8(px)
  Chart/4(mode) -> Terminator/1
  Mux/1 -> force/1
  Constant/1 -> Chart/1(kn)
  Constant1/1 -> Chart/2(kt)
  Constant2/1 -> Chart/3(bn)
  Constant3/1 -> Chart/4(bt)
  Constant4/1 -> Chart/5(mu_d)
  Constant5/1 -> Chart/6(mu_s)
  Constant6/1 -> Chart/7(zvt)

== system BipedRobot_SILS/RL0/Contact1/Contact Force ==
  pos : Inport
  vel : Inport  Port=2
  Chart : Stateflow chart  TreatAsAtomicUnit=on
  Constant : Constant  Value=kn
  Constant1 : Constant  Value=kt
  Constant2 : Constant  Value=bn
  Constant3 : Constant  Value=bt
  Constant4 : Constant  Value=mu_d
  Constant5 : Constant  Value=mu_s
  Constant6 : Constant  Value=zvt
  Demux : Demux  Outputs=3
  Demux1 : Demux  Outputs=3
  Mux : Mux  Inputs=3
  Terminator : Terminator
  force : Outport  InitialOutput=0
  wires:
  Chart/3(Fn) -> Mux/3, [FnR_FrontLeft]
  Chart/2(Fy) -> Mux/2
  Chart/1(Fx) -> Mux/1
  vel/1 -> Demux1/1
  pos/1 -> Demux/1
  Demux1/3 -> Chart/13(dpn)
  Demux1/2 -> Chart/12(dpy)
  Demux1/1 -> Chart/11(dpx)
  Demux/3 -> Chart/10(pn)
  Demux/2 -> Chart/9(py)
  Demux/1 -> Chart/8(px)
  Chart/4(mode) -> Terminator/1
  Mux/1 -> force/1
  Constant/1 -> Chart/1(kn)
  Constant1/1 -> Chart/2(kt)
  Constant2/1 -> Chart/3(bn)
  Constant3/1 -> Chart/4(bt)
  Constant4/1 -> Chart/5(mu_d)
  Constant5/1 -> Chart/6(mu_s)
  Constant6/1 -> Chart/7(zvt)

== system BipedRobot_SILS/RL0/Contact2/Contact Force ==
  pos : Inport
  vel : Inport  Port=2
  Chart : Stateflow chart  TreatAsAtomicUnit=on
  Constant : Constant  Value=kn
  Constant1 : Constant  Value=kt
  Constant2 : Constant  Value=bn
  Constant3 : Constant  Value=bt
  Constant4 : Constant  Value=mu_d
  Constant5 : Constant  Value=mu_s
  Constant6 : Constant  Value=zvt
  Demux : Demux  Outputs=3
  Demux1 : Demux  Outputs=3
  Mux : Mux  Inputs=3
  Terminator : Terminator
  force : Outport  InitialOutput=0
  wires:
  Chart/3(Fn) -> Mux/3, [FnR_RearLeft]
  Chart/2(Fy) -> Mux/2
  Chart/1(Fx) -> Mux/1
  vel/1 -> Demux1/1
  pos/1 -> Demux/1
  Demux1/3 -> Chart/13(dpn)
  Demux1/2 -> Chart/12(dpy)
  Demux1/1 -> Chart/11(dpx)
  Demux/3 -> Chart/10(pn)
  Demux/2 -> Chart/9(py)
  Demux/1 -> Chart/8(px)
  Chart/4(mode) -> Terminator/1
  Mux/1 -> force/1
  Constant/1 -> Chart/1(kn)
  Constant1/1 -> Chart/2(kt)
  Constant2/1 -> Chart/3(bn)
  Constant3/1 -> Chart/4(bt)
  Constant4/1 -> Chart/5(mu_d)
  Constant5/1 -> Chart/6(mu_s)
  Constant6/1 -> Chart/7(zvt)

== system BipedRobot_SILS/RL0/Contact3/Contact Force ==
  pos : Inport
  vel : Inport  Port=2
  Chart : Stateflow chart  TreatAsAtomicUnit=on
  Constant : Constant  Value=kn
  Constant1 : Constant  Value=kt
  Constant2 : Constant  Value=bn
  Constant3 : Constant  Value=bt
  Constant4 : Constant  Value=mu_d
  Constant5 : Constant  Value=mu_s
  Constant6 : Constant  Value=zvt
  Demux : Demux  Outputs=3
  Demux1 : Demux  Outputs=3
  Mux : Mux  Inputs=3
  Terminator : Terminator
  force : Outport  InitialOutput=0
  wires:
  Chart/3(Fn) -> Mux/3, [FnR_FrontRight]
  Chart/2(Fy) -> Mux/2
  Chart/1(Fx) -> Mux/1
  vel/1 -> Demux1/1
  pos/1 -> Demux/1
  Demux1/3 -> Chart/13(dpn)
  Demux1/2 -> Chart/12(dpy)
  Demux1/1 -> Chart/11(dpx)
  Demux/3 -> Chart/10(pn)
  Demux/2 -> Chart/9(py)
  Demux/1 -> Chart/8(px)
  Chart/4(mode) -> Terminator/1
  Mux/1 -> force/1
  Constant/1 -> Chart/1(kn)
  Constant1/1 -> Chart/2(kt)
  Constant2/1 -> Chart/3(bn)
  Constant3/1 -> Chart/4(bt)
  Constant4/1 -> Chart/5(mu_d)
  Constant5/1 -> Chart/6(mu_s)
  Constant6/1 -> Chart/7(zvt)

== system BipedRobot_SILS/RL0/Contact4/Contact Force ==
  pos : Inport
  vel : Inport  Port=2
  Chart : Stateflow chart  TreatAsAtomicUnit=on
  Constant : Constant  Value=kn
  Constant1 : Constant  Value=kt
  Constant2 : Constant  Value=bn
  Constant3 : Constant  Value=bt
  Constant4 : Constant  Value=mu_d
  Constant5 : Constant  Value=mu_s
  Constant6 : Constant  Value=zvt
  Demux : Demux  Outputs=3
  Demux1 : Demux  Outputs=3
  Mux : Mux  Inputs=3
  Terminator : Terminator
  force : Outport  InitialOutput=0
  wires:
  Chart/3(Fn) -> Mux/3, [FnR_RearRight]
  Chart/2(Fy) -> Mux/2
  Chart/1(Fx) -> Mux/1
  vel/1 -> Demux1/1
  pos/1 -> Demux/1
  Demux1/3 -> Chart/13(dpn)
  Demux1/2 -> Chart/12(dpy)
  Demux1/1 -> Chart/11(dpx)
  Demux/3 -> Chart/10(pn)
  Demux/2 -> Chart/9(py)
  Demux/1 -> Chart/8(px)
  Chart/4(mode) -> Terminator/1
  Mux/1 -> force/1
  Constant/1 -> Chart/1(kn)
  Constant1/1 -> Chart/2(kt)
  Constant2/1 -> Chart/3(bn)
  Constant3/1 -> Chart/4(bt)
  Constant4/1 -> Chart/5(mu_d)
  Constant5/1 -> Chart/6(mu_s)
  Constant6/1 -> Chart/7(zvt)

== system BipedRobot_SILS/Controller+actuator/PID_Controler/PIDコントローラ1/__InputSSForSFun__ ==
  ref : Inport
  pos : Inport  Port=2
  __UniqueOutportName__1__ : Outport
  __UniqueOutportName__2__ : Outport  Port=2
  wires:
  ref/1 -> __UniqueOutportName__1__/1
  pos/1 -> __UniqueOutportName__2__/1

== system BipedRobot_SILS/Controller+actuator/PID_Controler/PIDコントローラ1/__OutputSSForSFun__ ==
  __UniqueInportName__1__ : Inport
  out : Outport
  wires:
  __UniqueInportName__1__/1 -> out/1  "result"

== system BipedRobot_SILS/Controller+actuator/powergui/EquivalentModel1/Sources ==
  Mux : Mux  Inputs=1
  u : Outport
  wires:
  Mux/1 -> u/1
  [T75_6731_8330657178378] -> Mux/1

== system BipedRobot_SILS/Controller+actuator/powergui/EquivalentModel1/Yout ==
  v,i : Inport
  Demux : Demux  Outputs=1
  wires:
  v,i/1 -> Demux/1
  Demux/1 -> [T65_5940_6291244306635]

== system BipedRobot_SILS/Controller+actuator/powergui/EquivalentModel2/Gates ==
  Mux : Mux  Inputs=[1 1 1 1 1 1 1 1]
  gates : Outport
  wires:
  Mux/1 -> gates/1
  [T69_6416_7410491432690] -> Mux/1
  [T70_6465_7542578735271] -> Mux/2
  [T70_6466_7540903108789] -> Mux/3
  [T70_6467_7539356890592] -> Mux/4
  [T62_5764_5743424616372] -> Mux/5
  [T63_5813_5801375769299] -> Mux/6
  [T63_5814_5800460189498] -> Mux/7
  [T63_5815_5799688396682] -> Mux/8

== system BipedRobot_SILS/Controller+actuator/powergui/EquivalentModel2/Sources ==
  Mux : Mux  Inputs=[1 1]
  Mux_u : Mux  Inputs=[8 2]
  SwitchCurrents : Constant  Value=zeros(8,1)
  u : Outport
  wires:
  Mux/1 -> Mux_u/2
  SwitchCurrents/1 -> Mux_u/1
  Mux_u/1 -> u/1
  [T67_6156_6955295286753] -> Mux/1
  [T65_5800_5246919186788] -> Mux/2

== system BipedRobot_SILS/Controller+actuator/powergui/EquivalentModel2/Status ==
  status : Inport
  Demux : Demux  Outputs=[1 1 1 1 1 1 1 1]
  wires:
  status/1 -> Demux/1
  Demux/1 -> [T71_6651_8311672862748]
  Demux/2 -> [T72_6700_8474473300843]
  Demux/3 -> [T72_6701_8472493370915]
  Demux/4 -> [T72_6702_8470639254599]
  Demux/5 -> [T64_5999_6565696543728]
  Demux/6 -> [T65_6048_6657818177462]
  Demux/7 -> [T65_6049_6656540163404]
  Demux/8 -> [T65_6050_6655401512115]

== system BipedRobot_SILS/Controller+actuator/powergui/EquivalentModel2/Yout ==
  v,i : Inport
  Demux : Demux  Outputs=[1 1 1 1 1 1 1 1 1]
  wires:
  v,i/1 -> Demux/1
  Demux/1 -> [T72_6750_8477745249452]
  Demux/2 -> [T73_6799_8649744029475]
  Demux/3 -> [T73_6800_8647665284079]
  Demux/4 -> [T73_6801_8645710628820]
  Demux/5 -> [T65_6098_6717574178135]
  Demux/6 -> [T66_6147_6820275366536]
  Demux/7 -> [T66_6148_6818876820767]
  Demux/8 -> [T66_6149_6817615526210]
  Demux/9 -> [T65_5935_6276725906034]

== stateflow chart BipedRobot_SILS/RL0/Contact1/Contact
Force/Chart ==
  state No_Contact/
    state 非接触状態 [group]
    (default) -> (junction 48) : { mode = 1;  /* 垂直力、摩擦力ともにゼロ */ Fn = 0; Fx = 0; Fy = 0; }
  state Sticking/
    state 固着状態 [group]
    Sticking -> (junction 53) : { /* 垂直力計算 */ Fn = -(kn*pn+bn*dpn); }
    (default) -> (junction 52) : { mode = 4;  /* 垂直力計算 */ Fn = -(kn*pn+bn*dpn); }
    (junction 52) -> (junction 53)
    (junction 53) -> (junction 54) : [ Fn < 0 ]
    (junction 53) -> (junction 41) : { /* 静止摩擦力計算 */ Fx = -(kt*(px-ax)+bt*dpx); Fy = -(kt*(py-ay)+bt*dpy);  /* 摩擦力ベクトルの大きさ */ norm_Ft = sqrt(Fx^2+Fy^2); }
    (junction 54) -> (junction 47) : { mode = 6;  /* 垂直力が負のときの処理 垂直力、摩擦力をゼロへ */ Fn = 0; Fx = 0; Fy = 0; }
    (junction 41) -> (junction 40) : [ norm_Ft > mu_s*Fn ]
    (junction 41) -> (junction 39)
    (junction 40) -> (junction 38) : { mode = 5;  /* 静止摩擦力計算 */ Fx = -mu_s*Fn*Fx/norm_Ft; Fy = -mu_s*Fn*Fy/norm_Ft; }
    (junction 38) -> (junction 39)
    (junction 47) -> (junction 38)
    (junction 39) -> (junction 56)
  state Sliding/
    state 滑り状態 [group]
    Sliding -> (junction 43) : { mode = 2;  /* 垂直力計算 */ Fn = -(kn*pn+bn*dpn); }
    (default) -> (junction 42) : { mode = 2;  /* 垂直力計算 */ Fn = -(kn*pn+bn*dpn); }
    (junction 42) -> (junction 43)
    (junction 43) -> (junction 44) : [ Fn < 0 ]
    (junction 43) -> (junction 45) : { /* 接線方向速度ベクトルの大きさ */ norm_dpt = sqrt(dpx^2+dpy^2); }
    (junction 44) -> (junction 46) : { mode = 6;  /* 垂直力が負のときの処理 垂直力、摩擦力をゼロへ */ Fn = 0; Fx = 0; Fy = 0; }
    (junction 45) -> (junction 49) : [ norm_dpt <= zvt ]
    (junction 45) -> (junction 51) : { /* 動摩擦力計算 */ Fx = -mu_d*Fn*dpx/norm_dpt; Fy = -mu_d*Fn*dpy/norm_dpt; }
    (junction 49) -> (junction 50) : { mode = 3;  /* 動摩擦力計算 */ Fx = -mu_d*Fn*dpx/zvt; Fy = -mu_d*Fn*dpy/zvt;  /* アンカーポイント設定 */ ax = px; ay = py; }
    (junction 50) -> (junction 51)
    (junction 46) -> (junction 50)
    (junction 51) -> (junction 55)
  (default) -> No_Contact
  Sliding -> No_Contact : [pn >= 0 ]
  No_Contact -> Sliding : [ pn < 0 ]
  Sticking -> No_Contact : [ pn >= 0 ]
  Sliding -> Sticking : [ pn < 0 ... && mode == 3 ]
  Sticking -> Sliding : [ pn < 0 ... && (mode == 5 || mode == 6) ]
  data: Fx output double; Fy output double; kn input =kn; kt input =kt; bn input =bn; bt input =bt; mu_d input =mu_d; mu_s input =mu_s; zvt input =zvt; px input; py input; pn input; dpx input; dpy input; Fn output double; dpn input; norm_dpt local double; norm_Ft local double; mode output double; ax local double; ay local double

== stateflow chart BipedRobot_SILS/RL0/Contact2/Contact
Force/Chart ==
  state No_Contact/
    state 非接触状態 [group]
    (default) -> (junction 48) : { mode = 1;  /* 垂直力、摩擦力ともにゼロ */ Fn = 0; Fx = 0; Fy = 0; }
  state Sticking/
    state 固着状態 [group]
    Sticking -> (junction 53) : { /* 垂直力計算 */ Fn = -(kn*pn+bn*dpn); }
    (default) -> (junction 52) : { mode = 4;  /* 垂直力計算 */ Fn = -(kn*pn+bn*dpn); }
    (junction 52) -> (junction 53)
    (junction 53) -> (junction 54) : [ Fn < 0 ]
    (junction 53) -> (junction 41) : { /* 静止摩擦力計算 */ Fx = -(kt*(px-ax)+bt*dpx); Fy = -(kt*(py-ay)+bt*dpy);  /* 摩擦力ベクトルの大きさ */ norm_Ft = sqrt(Fx^2+Fy^2); }
    (junction 54) -> (junction 47) : { mode = 6;  /* 垂直力が負のときの処理 垂直力、摩擦力をゼロへ */ Fn = 0; Fx = 0; Fy = 0; }
    (junction 41) -> (junction 40) : [ norm_Ft > mu_s*Fn ]
    (junction 41) -> (junction 39)
    (junction 40) -> (junction 38) : { mode = 5;  /* 静止摩擦力計算 */ Fx = -mu_s*Fn*Fx/norm_Ft; Fy = -mu_s*Fn*Fy/norm_Ft; }
    (junction 38) -> (junction 39)
    (junction 47) -> (junction 38)
    (junction 39) -> (junction 56)
  state Sliding/
    state 滑り状態 [group]
    Sliding -> (junction 43) : { mode = 2;  /* 垂直力計算 */ Fn = -(kn*pn+bn*dpn); }
    (default) -> (junction 42) : { mode = 2;  /* 垂直力計算 */ Fn = -(kn*pn+bn*dpn); }
    (junction 42) -> (junction 43)
    (junction 43) -> (junction 44) : [ Fn < 0 ]
    (junction 43) -> (junction 45) : { /* 接線方向速度ベクトルの大きさ */ norm_dpt = sqrt(dpx^2+dpy^2); }
    (junction 44) -> (junction 46) : { mode = 6;  /* 垂直力が負のときの処理 垂直力、摩擦力をゼロへ */ Fn = 0; Fx = 0; Fy = 0; }
    (junction 45) -> (junction 49) : [ norm_dpt <= zvt ]
    (junction 45) -> (junction 51) : { /* 動摩擦力計算 */ Fx = -mu_d*Fn*dpx/norm_dpt; Fy = -mu_d*Fn*dpy/norm_dpt; }
    (junction 49) -> (junction 50) : { mode = 3;  /* 動摩擦力計算 */ Fx = -mu_d*Fn*dpx/zvt; Fy = -mu_d*Fn*dpy/zvt;  /* アンカーポイント設定 */ ax = px; ay = py; }
    (junction 50) -> (junction 51)
    (junction 46) -> (junction 50)
    (junction 51) -> (junction 55)
  (default) -> No_Contact
  Sliding -> No_Contact : [pn >= 0 ]
  No_Contact -> Sliding : [ pn < 0 ]
  Sticking -> No_Contact : [ pn >= 0 ]
  Sliding -> Sticking : [ pn < 0 ... && mode == 3 ]
  Sticking -> Sliding : [ pn < 0 ... && (mode == 5 || mode == 6) ]
  data: Fx output double; Fy output double; kn input =kn; kt input =kt; bn input =bn; bt input =bt; mu_d input =mu_d; mu_s input =mu_s; zvt input =zvt; px input; py input; pn input; dpx input; dpy input; Fn output double; dpn input; norm_dpt local double; norm_Ft local double; mode output double; ax local double; ay local double

== stateflow chart BipedRobot_SILS/RL0/Contact3/Contact
Force/Chart ==
  state No_Contact/
    state 非接触状態 [group]
    (default) -> (junction 48) : { mode = 1;  /* 垂直力、摩擦力ともにゼロ */ Fn = 0; Fx = 0; Fy = 0; }
  state Sticking/
    state 固着状態 [group]
    Sticking -> (junction 53) : { /* 垂直力計算 */ Fn = -(kn*pn+bn*dpn); }
    (default) -> (junction 52) : { mode = 4;  /* 垂直力計算 */ Fn = -(kn*pn+bn*dpn); }
    (junction 52) -> (junction 53)
    (junction 53) -> (junction 54) : [ Fn < 0 ]
    (junction 53) -> (junction 41) : { /* 静止摩擦力計算 */ Fx = -(kt*(px-ax)+bt*dpx); Fy = -(kt*(py-ay)+bt*dpy);  /* 摩擦力ベクトルの大きさ */ norm_Ft = sqrt(Fx^2+Fy^2); }
    (junction 54) -> (junction 47) : { mode = 6;  /* 垂直力が負のときの処理 垂直力、摩擦力をゼロへ */ Fn = 0; Fx = 0; Fy = 0; }
    (junction 41) -> (junction 40) : [ norm_Ft > mu_s*Fn ]
    (junction 41) -> (junction 39)
    (junction 40) -> (junction 38) : { mode = 5;  /* 静止摩擦力計算 */ Fx = -mu_s*Fn*Fx/norm_Ft; Fy = -mu_s*Fn*Fy/norm_Ft; }
    (junction 38) -> (junction 39)
    (junction 47) -> (junction 38)
    (junction 39) -> (junction 56)
  state Sliding/
    state 滑り状態 [group]
    Sliding -> (junction 43) : { mode = 2;  /* 垂直力計算 */ Fn = -(kn*pn+bn*dpn); }
    (default) -> (junction 42) : { mode = 2;  /* 垂直力計算 */ Fn = -(kn*pn+bn*dpn); }
    (junction 42) -> (junction 43)
    (junction 43) -> (junction 44) : [ Fn < 0 ]
    (junction 43) -> (junction 45) : { /* 接線方向速度ベクトルの大きさ */ norm_dpt = sqrt(dpx^2+dpy^2); }
    (junction 44) -> (junction 46) : { mode = 6;  /* 垂直力が負のときの処理 垂直力、摩擦力をゼロへ */ Fn = 0; Fx = 0; Fy = 0; }
    (junction 45) -> (junction 49) : [ norm_dpt <= zvt ]
    (junction 45) -> (junction 51) : { /* 動摩擦力計算 */ Fx = -mu_d*Fn*dpx/norm_dpt; Fy = -mu_d*Fn*dpy/norm_dpt; }
    (junction 49) -> (junction 50) : { mode = 3;  /* 動摩擦力計算 */ Fx = -mu_d*Fn*dpx/zvt; Fy = -mu_d*Fn*dpy/zvt;  /* アンカーポイント設定 */ ax = px; ay = py; }
    (junction 50) -> (junction 51)
    (junction 46) -> (junction 50)
    (junction 51) -> (junction 55)
  (default) -> No_Contact
  Sliding -> No_Contact : [pn >= 0 ]
  No_Contact -> Sliding : [ pn < 0 ]
  Sticking -> No_Contact : [ pn >= 0 ]
  Sliding -> Sticking : [ pn < 0 ... && mode == 3 ]
  Sticking -> Sliding : [ pn < 0 ... && (mode == 5 || mode == 6) ]
  data: Fx output double; Fy output double; kn input =kn; kt input =kt; bn input =bn; bt input =bt; mu_d input =mu_d; mu_s input =mu_s; zvt input =zvt; px input; py input; pn input; dpx input; dpy input; Fn output double; dpn input; norm_dpt local double; norm_Ft local double; mode output double; ax local double; ay local double

== stateflow chart BipedRobot_SILS/RL0/Contact4/Contact
Force/Chart ==
  state No_Contact/
    state 非接触状態 [group]
    (default) -> (junction 48) : { mode = 1;  /* 垂直力、摩擦力ともにゼロ */ Fn = 0; Fx = 0; Fy = 0; }
  state Sticking/
    state 固着状態 [group]
    Sticking -> (junction 53) : { /* 垂直力計算 */ Fn = -(kn*pn+bn*dpn); }
    (default) -> (junction 52) : { mode = 4;  /* 垂直力計算 */ Fn = -(kn*pn+bn*dpn); }
    (junction 52) -> (junction 53)
    (junction 53) -> (junction 54) : [ Fn < 0 ]
    (junction 53) -> (junction 41) : { /* 静止摩擦力計算 */ Fx = -(kt*(px-ax)+bt*dpx); Fy = -(kt*(py-ay)+bt*dpy);  /* 摩擦力ベクトルの大きさ */ norm_Ft = sqrt(Fx^2+Fy^2); }
    (junction 54) -> (junction 47) : { mode = 6;  /* 垂直力が負のときの処理 垂直力、摩擦力をゼロへ */ Fn = 0; Fx = 0; Fy = 0; }
    (junction 41) -> (junction 40) : [ norm_Ft > mu_s*Fn ]
    (junction 41) -> (junction 39)
    (junction 40) -> (junction 38) : { mode = 5;  /* 静止摩擦力計算 */ Fx = -mu_s*Fn*Fx/norm_Ft; Fy = -mu_s*Fn*Fy/norm_Ft; }
    (junction 38) -> (junction 39)
    (junction 47) -> (junction 38)
    (junction 39) -> (junction 56)
  state Sliding/
    state 滑り状態 [group]
    Sliding -> (junction 43) : { mode = 2;  /* 垂直力計算 */ Fn = -(kn*pn+bn*dpn); }
    (default) -> (junction 42) : { mode = 2;  /* 垂直力計算 */ Fn = -(kn*pn+bn*dpn); }
    (junction 42) -> (junction 43)
    (junction 43) -> (junction 44) : [ Fn < 0 ]
    (junction 43) -> (junction 45) : { /* 接線方向速度ベクトルの大きさ */ norm_dpt = sqrt(dpx^2+dpy^2); }
    (junction 44) -> (junction 46) : { mode = 6;  /* 垂直力が負のときの処理 垂直力、摩擦力をゼロへ */ Fn = 0; Fx = 0; Fy = 0; }
    (junction 45) -> (junction 49) : [ norm_dpt <= zvt ]
    (junction 45) -> (junction 51) : { /* 動摩擦力計算 */ Fx = -mu_d*Fn*dpx/norm_dpt; Fy = -mu_d*Fn*dpy/norm_dpt; }
    (junction 49) -> (junction 50) : { mode = 3;  /* 動摩擦力計算 */ Fx = -mu_d*Fn*dpx/zvt; Fy = -mu_d*Fn*dpy/zvt;  /* アンカーポイント設定 */ ax = px; ay = py; }
    (junction 50) -> (junction 51)
    (junction 46) -> (junction 50)
    (junction 51) -> (junction 55)
  (default) -> No_Contact
  Sliding -> No_Contact : [pn >= 0 ]
  No_Contact -> Sliding : [ pn < 0 ]
  Sticking -> No_Contact : [ pn >= 0 ]
  Sliding -> Sticking : [ pn < 0 ... && mode == 3 ]
  Sticking -> Sliding : [ pn < 0 ... && (mode == 5 || mode == 6) ]
  data: Fx output double; Fy output double; kn input =kn; kt input =kt; bn input =bn; bt input =bt; mu_d input =mu_d; mu_s input =mu_s; zvt input =zvt; px input; py input; pn input; dpx input; dpy input; Fn output double; dpn input; norm_dpt local double; norm_Ft local double; mode output double; ax local double; ay local double
